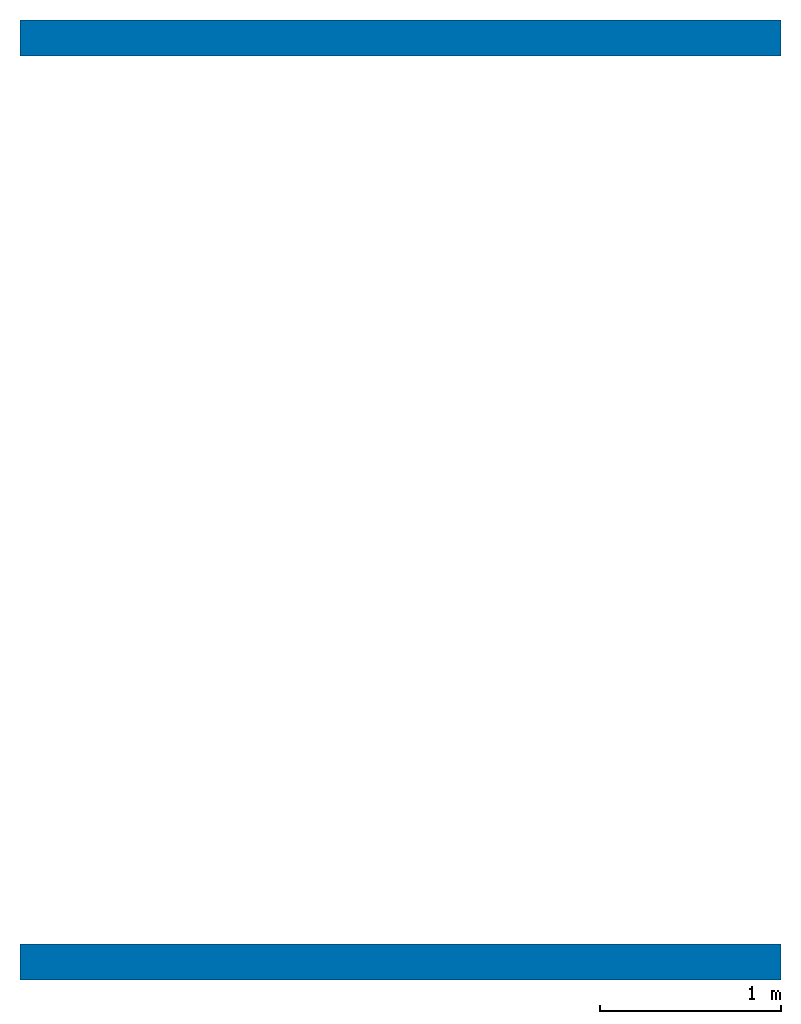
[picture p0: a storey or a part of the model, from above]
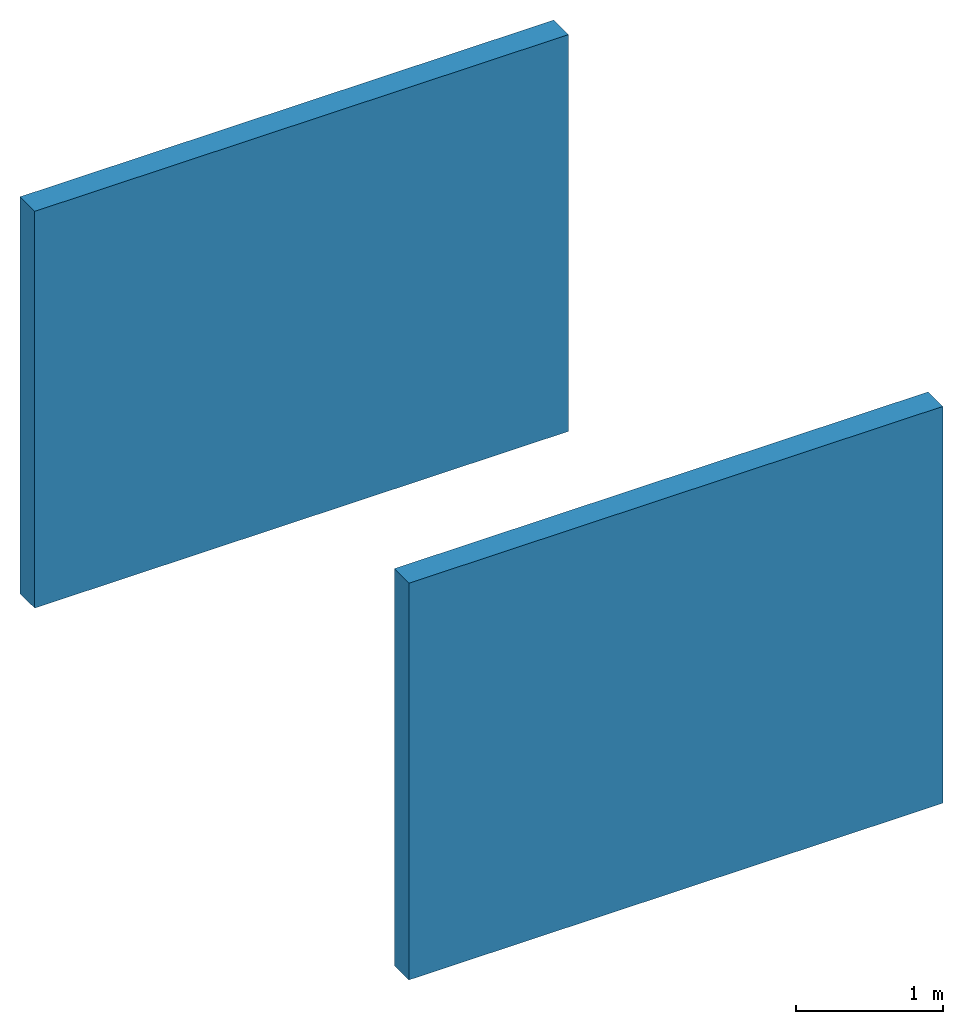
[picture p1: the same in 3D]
Properties of the parts of a building model (IFC4)

# File
Description: ViewDefinition [ReferenceView_V1.2], RevitIdentifiers [ContentGUID: , VersionGUID: 488d4783-6c16-4759-8540-48bcfd5ee86a, NumberOfSaves: 76], CoordinateReference [CoordinateBase: Project Base Point, ProjectSite: Internal]
File name: [V-code]_([context]-[cluster]-[discipline])_(concept-aanzet).ifc
Time: 2025-09-28T15:26:29+01:00
Written by: ODA SDAI 22.12
Made in: Autodesk Revit 23.1.80.30 (ENU) - IFC 23.4.1.0

# IfcProject, [ProjectCode]
LongName: [ProjectNaam]
RBS - Name: [ProjectCode]; LongName: [ProjectNaam]; OS link: [OS link]

# IfcSite, [ComplexCode]
LongName: [ComplexNaam]; RefLatitude: 52, 4, 57, 468566; RefLongitude: 4, 19, 1, 452026; RefElevation: 0 mm
Pset_SiteCommon - Reference: Project Information
RBS - Name: [ComplexCode]; LongName: [ComplexNaam]; SiteAddress: [Straatnaam] [Huisnummer] [Huisnummer toev.],[Postcode] [Plaatsnaam],[Land]; TrueNorth: 0 deg
Other - Category: Project Information; Project Address: [Straatnaam] [Huisnummer] [Huisnummer toev.],[Postcode] [Plaatsnaam],[Land]; Project Name: [ProjectNaam]; Project Number: [ProjectCode]
Constraints - TrueNorth: 0 deg
Data - RBS_OS_link: [OS link]
Identity Data - BuildingLongName: [BouwwerkNaam]; Building Name: [BouwwerkCode]; RBS_opdrachtnemer_bedrijf_adres: [ON BedrijfsAdres]; RBS_opdrachtnemer_bedrijf_naam: [ON BedrijfsNaam]; RBS_opdrachtnemer_project_code: [ON ProjectCode]; RBS_vastgoed_deel_code: [BouwwerkDeelCode]; SiteLongName: [ComplexNaam]; SiteName: [ComplexCode]

# IfcBuilding, [BouwwerkCode]
LongName: [BouwwerkNaam]
Pset_BuildingCommon - Reference: Project Information; NumberOfStoreys: 4
Pset_BuildingElementProxyCommon - Reference: Project Information; IsExternal: no
Pset_BuildingStoreyCommon - Reference: Project Information; sets with these values: 2
RBS - Name: [BouwwerkCode]; LongName: [BouwwerkNaam]
Other - Category: Project Information; Project Address: [Straatnaam] [Huisnummer] [Huisnummer toev.],[Postcode] [Plaatsnaam],[Land]; Project Name: [ProjectNaam]; Project Number: [ProjectCode]
Constraints - TrueNorth: 0 deg
Data - RBS_OS_link: [OS link]
Identity Data - BuildingLongName: [BouwwerkNaam]; Building Name: [BouwwerkCode]; RBS_opdrachtnemer_bedrijf_adres: [ON BedrijfsAdres]; RBS_opdrachtnemer_bedrijf_naam: [ON BedrijfsNaam]; RBS_opdrachtnemer_project_code: [ON ProjectCode]; RBS_vastgoed_deel_code: [BouwwerkDeelCode]; SiteLongName: [ComplexNaam]; SiteName: [ComplexCode]

# IfcBuildingStorey: bouwlaag (4)
In: [BouwwerkCode]
Pset_BuildingStoreyCommon - EntranceLevel: no
RBS - Structural: no
Other - Category: Levels; Family: Level
Data - EntranceLevel: no
Dimensions - Computation Height: 0 mm
Identity Data - Structural: no
Other(Type) - Category: Levels; Family Name: Level
Constraints(Type) - Elevation Base: Project Base Point
Graphics(Type) - Line Pattern: Dash=2_Space=1_Dot_Space=1; Line Weight: 1
Name | LongName | Elevation (mm) = RBS, Elevation (mm) = Constraints, Elevation (mm) | Reference = Type = Type Name | Pset_BuildingStoreyCommon, AboveGround = Data, AboveGround | RBS, Name = IfcName | RBS, LongName = IfcLongName | Family and Type | Type Id | Building Story = Symbol at End 1 Default | Identity Data, Name | Color | Symbol | Symbol at End 2 Default | IfcObjectType[Type]
-1 | kelder | -3300 | vloer-afgewerkt-BK_bouwlaag | no | -1 | kelder | Level: vloer-afgewerkt-BK_bouwlaag | 2863 | yes | -1_kelder_(AVL-BK) | 13073152 | RBS_--_LAB_Elevation Head : AVL-BK | no | bouwlaag | Constraints - Story Above: 00_begane grond_(AVL-BK)
00 | begane grond | 0 | maaiveld | yes |  |  | Level: maaiveld | 2905 | no | terrein | 821049 | RBS_--_LAB_Elevation Head : MV | yes
01 | verdieping | 3300 | vloer-afgewerkt-BK_bouwlaag | yes | 01 | verdieping | Level: vloer-afgewerkt-BK_bouwlaag | 2863 | yes | 01_eerste verdieping_(AVL-BK) | 13073152 | RBS_--_LAB_Elevation Head : AVL-BK | no | bouwlaag | Constraints - Story Above: 02_tweede verdieping_(AVL-BK)
02 | verdieping | 6600 | vloer-afgewerkt-BK_bouwlaag | yes | 02 | verdieping | Level: vloer-afgewerkt-BK_bouwlaag | 2863 | yes | 02_tweede verdieping_(AVL-BK) | 13073152 | RBS_--_LAB_Elevation Head : AVL-BK | no | bouwlaag

# IfcBuildingStorey: bouwlaag_tussen, 01t
In: [BouwwerkCode]
LongName: tussenverdieping; Elevation: 4800 mm
Pset_BuildingStoreyCommon - EntranceLevel: no; AboveGround: yes; Reference: vloer-afgewerkt-BK_bouwlaag_tussen
RBS - Structural: no; Name: 01t; LongName: tussenverdieping; Elevation: 4800 mm
Other - Category: Levels; Family: Level; Family and Type: Level: vloer-afgewerkt-BK_bouwlaag_tussen; Type: vloer-afgewerkt-BK_bouwlaag_tussen; Type Id: 2880
Constraints - Elevation: 4800 mm
Data - EntranceLevel: no; AboveGround: yes
Dimensions - Computation Height: 0 mm
Identity Data - Structural: no; Building Story: yes; IfcLongName: tussenverdieping; IfcName: 01t; Name: 01t_eerste verdieping_(AVL-BK)
Other(Type) - Category: Levels; Family Name: Level
Constraints(Type) - Elevation Base: Project Base Point
Graphics(Type) - Line Pattern: Dash=2_Space=1_Dot_Space=1; Line Weight: 1; Symbol: RBS_--_LAB_Elevation Head : AVL-BK; Symbol at End 1 Default: yes; Symbol at End 2 Default: no; Color: 13073152
Identity Data(Type) - IfcObjectType[Type]: bouwlaag_tussen; Type Name: vloer-afgewerkt-BK_bouwlaag_tussen

# IfcBuildingStorey: bouwlaagoppervlaklaag (2)
In: [BouwwerkCode]
Pset_BuildingStoreyCommon - EntranceLevel: no; Reference: registratief-oppervlak; AboveGround: yes
RBS - Structural: no
Other - Category: Levels; Family: Level; Family and Type: Level: registratief-oppervlak; Type: registratief-oppervlak; Type Id: 2917
Data - EntranceLevel: no; AboveGround: yes
Dimensions - Computation Height: 0 mm
Identity Data - Structural: no; Building Story: yes
Other(Type) - Category: Levels; Family Name: Level
Constraints(Type) - Elevation Base: Project Base Point
Graphics(Type) - Line Pattern: Dash=2_Space=1_Dot_Space=1; Line Weight: 1; Symbol at End 1 Default: yes; Symbol at End 2 Default: no; Color: 13073152; Symbol: RBS_--_LAB_Elevation Head : RO
Identity Data(Type) - IfcObjectType[Type]: bouwlaagoppervlaklaag; Type Name: registratief-oppervlak
Name | LongName = Identity Data, Name | Elevation (mm) = RBS, Elevation (mm) = Constraints, Elevation (mm) | RBS, Name = IfcName
00 | 00_bouwlaagoppervlak | 0 | 00 | Constraints - Story Above: 01_bouwlaagoppervlak
01 | 01_bouwlaagoppervlak | 3300 | 01

# IfcSpace: 00.001 (2)
In: 00
Pset_SpaceCommon - IsExternal: no
RBS - IsExternal: no; Name: 00.001
Qto_SpaceBaseQuantities - Height: 3300 mm
Construction - IsExternal: no
Dimensions - Computation Height: 0 mm
Identity Data - IfcName: 00.001; Number: 00.001 (projectspecifiek)
Name | LongName = RBS, LongName = ObjectType = IfcLongName = IfcObjectType | Pset_SpaceCommon, Reference = Pset_SpaceHeaterTypeCommon, Reference | ElementId | GrossFloorArea (m2) = NetFloorArea (m2) = GrossCeilingArea (m2) = Area (m2) | Category | Level | Perimeter (mm) | Name
00.001 | ruimte | ruimte (projectspecifiek) 00.001 (projectspecifiek) | 697761 | 19.6 | Rooms | 00_begane grond_(AVL-BK) | 17800 | ruimte (projectspecifiek) | Qto_SpaceBaseQuantities - GrossVolume: 58.8 m3; NetVolume: 58.8 m3; Other - Phase Id: 3; Constraints - Base Offset: 0 mm; Limit Offset: 0 mm; Upper Limit: 01_eerste verdieping_(AVL-BK); Dimensions - Unbounded Height: 3300 mm; Volume: 58.8 m3; Energy Analysis - Actual Lighting Load: 0 W; Actual Lighting Load per area: 0; Actual Power Load: 0 W; Actual Power Load per area: 0; Area per Person: 28.5714 m2; Base Lighting Load on: By Space Type; Base Power Load on: By Space Type; Heat Load Values: By Space Type; Latent Heat Gain per person: 58.6142 W; Lighting Load Units: Power Density; Number of People: 0; Plenum Lighting Contribution: 0.2; Power Load Units: Power Density; Sensible Heat Gain per person: 73.2678 W; Specified Lighting Load: 0 W; Specified Lighting Load per area: 10.7639; Specified Power Load: 0 W; Specified Power Load per area: 13.9931; Total Heat Gain per person: 131.882 W; Phasing - Phase: nieuw
00.001 | bouwlaagoppervlak | bouwlaagoppervlak (projectspecifiek) 00.001 (projectspecifiek) | 697809 | 22.26 | Areas | 00_bouwlaagoppervlak | 19000 | bouwlaagoppervlak (projectspecifiek) | Other - Area Scheme Id: 2033; Area Type: Gross Building Area; Group: Gross Building

# IfcAirTerminal: Air Terminals : RBS_57_AT_ventilatierooster_BUVA_SH : Acoustream_65
In: 00
Type - PredefinedType: GRILLE; Classification: 57.10 luchtbehandeling; natuurlijk, algemeen (verzamelniveau) (NL-SfB); Material: divers
Type - Other - Category: Air Terminals; Family Name: RBS_57_AT_ventilatierooster_BUVA_SH
Type - Constraints - Default Elevation: 0.0131234 mm
Type - Dimensions - ventilatierooster_dikte: 15 mm; ventilatierooster_hoogte: 67.2153 mm; ventilatierooster_stelruimte_hout: 5 mm
Type - Identity Data - Assembly Code: 57.10; Assembly Description: luchtbehandeling; natuurlijk, algemeen (verzamelniveau); Description: PD-06022-Acoustream-65; IfcObjectType[Type]: ventilatierooster; Manufacturer: BUVA; Type Name: Acoustream_65
Type - Materials and Finishes - materiaal_onderdorpel: RBS_divers_gen
Type - Structural - LoadBearing: no; Structural: no
Type - Pset_ManufacturerTypeInformation - Manufacturer: BUVA
Type - RBS - IsExternal: yes; LoadBearing: no; Description: PD-06022-Acoustream-65; ObjectType: ventilatierooster; PredefinedType: GRILLE; Class: IfcAirTerminalType
Pset_AirTerminalBoxTypeCommon - Reference: Acoustream_65; sets with these values: 3
Qto_AirTerminalBaseQuantities - Perimeter: 457.047 mm
Other - Family: RBS_57_AT_ventilatierooster_BUVA_SH; Family and Type: RBS_57_AT_ventilatierooster_BUVA_SH: Acoustream_65; Type: Acoustream_65; Type Id: 645236
Constraints - Level: 00_begane grond_(AVL-BK); Moves With Nearby Elements: no; Elevation from Level: 2452.78 mm; Host: Level : 00_begane grond_(AVL-BK); Offset from Host: 2452.78 mm
Dimensions - Area: 0.212508 m2; kozijn_inbouwmaat: 900 mm; ventilatierooster_lengte: 890 mm; Volume: 0.0081186 m3
Identity Data - Assembly Name: kozijncombinatie_buiten; Mark: 2
Phasing - Phase Created: nieuw

# IfcBuildingElementProxy: Generic Models : RBS_--_GM_coördinatiepunt : peildatum_UIT, coördinatiepunt
In: [ComplexCode]
Type - PredefinedType: USERDEFINED; Classification: --.-- niet van toepassing (NL-SfB); Material: generiek - kleur (2)
Type - Other - Category: Generic Models; Family Name: RBS_--_GM_coördinatiepunt
Type - Dimensions - discipline_dikte: 25 mm
Type - Graphics - zichtbaar_discipline_B: no; zichtbaar_discipline_C: no; zichtbaar_discipline_E: no; zichtbaar_discipline_W: no; zichtbaar_peildatum: no
Type - Identity Data - Assembly Code: --.--; Assembly Description: niet van toepassing; IfcObjectType[Type]: coördinatiepunt; Type Name: peildatum_UIT
Type - Materials and Finishes - materiaal_discipline: RBS_kleur_wit_RGB (255-255-255); materiaal_kubus_basis: RBS_kleur_blauw_RGB (000-123-199); materiaal_kubus_hoek: RBS_kleur_rood_RGB (213-043-030); materiaal_peildatum: RBS_kleur_wit_RGB (255-255-255)
Type - RBS - ObjectType: coördinatiepunt; PredefinedType: USERDEFINED; Class: IfcBuildingElementProxyType
Pset_BuildingElementProxyCommon - IsExternal: no; Reference: peildatum_UIT
Pset_EnvironmentalImpactIndicators - Reference: peildatum_UIT
RBS - Name: coördinatiepunt; ElementId: 692979; SpatialContainer: IfcSite
Qto_BuildingElementProxyQuantities - NetSurfaceArea: 6.06928 m2; NetVolume: 1 m3
Other - Family: RBS_--_GM_coördinatiepunt; Family and Type: RBS_--_GM_coördinatiepunt: peildatum_UIT; Type: peildatum_UIT; Type Id: 692949
Constraints - Elevation from Level: 0 mm; Moves With Nearby Elements: no; Offset from Host: 0 mm; Host: Level : projectpeil=0; IfcSpatialContainer: IfcSite; Level: projectpeil=0
Data - RBS_VIP_datum_peil: dd-mm-jjjj
Dimensions - Area: 3.26796 m2; Volume: 1 m3
Identity Data - IfcName: coördinatiepunt
Phasing - Phase Created: nieuw

# IfcDoor: Doors : RBS_31_DO_deur_buiten_stomp_glas_1_paneel_SH : linksdraaiend
In: 00
Type - PredefinedType: DOOR; OperationType: SINGLE_SWING_RIGHT; Classification: 31.40 buitenwandopeningen; gevuld met puien, algemeen (verzamelniveau) (NL-SfB); Material: glas, hout
Type - Doors : RBS_31_DO_deur_buiten_stomp_glas_1_paneel_SH : linksdraaiend:1 - PanelOperation: SWINGING
Type - Other - Category: Doors; draairichting: RBS_3-_GM_deur_stomp_glas_draairichting_N : linksdraaiend; Family Name: RBS_31_DO_deur_buiten_stomp_glas_1_paneel_SH
Type - Constraints - Default Elevation: 0 mm
Type - Construction - Function: Exterior
Type - Identity Data - Assembly Code: 31.40; Assembly Description: buitenwandopeningen; gevuld met puien, algemeen (verzamelniveau); IfcExportAs[Type]: IfcDoor; IfcObjectType[Type]: deur; Type Mark: 11; Type Name: linksdraaiend
Type - Analytical Properties - Define Thermal Properties by: Schematic Type; Analytic Construction: <None>
Type - RBS - IsExternal: yes; ObjectType: deur; OperationType: SINGLE_SWING_RIGHT; Class: IfcDoor
OverallHeight: 1010 mm; OverallWidth: 930 mm
Pset_DoorCommon - IsExternal: yes; Reference: linksdraaiend
Pset_EnvironmentalImpactIndicators - Reference: linksdraaiend
Qto_DoorBaseQuantities - Width: 2015 mm; Height: 930 mm; Perimeter: 5890 mm; Area: 2.31905 m2
Other - Family: RBS_31_DO_deur_buiten_stomp_glas_1_paneel_SH; Family and Type: RBS_31_DO_deur_buiten_stomp_glas_1_paneel_SH: linksdraaiend; Type: linksdraaiend; Type Id: 645223
Constraints - Level: 00_begane grond_(AVL-BK); Moves With Nearby Elements: no; Host: Level : 00_begane grond_(AVL-BK); Offset from Host: 80 mm
Dimensions - Area: 2.31905 m2; b_glas: 630 mm; b_paneel: 930 mm; b_paneel_bovendorpel: 150 mm; b_paneel_onderdorpel: 400 mm; b_paneel_stijlen: 150 mm; d_glas: 20 mm; d_paneel: 80 mm; h_glas: 1465 mm; h_paneel: 2015 mm; Volume: 0.094539 m3
Identity Data - Assembly Name: kozijncombinatie_buiten; Mark: 1
Materials and Finishes - materiaal_glas: RBS_glas_afwerking_dubbel glas_floatglas; materiaal_paneel: RBS_hout_massief_vuren
Phasing - Phase Created: nieuw

# IfcElementAssembly: Assemblies : Generic Models Assembly : kozijncombinatie_buiten
In: 00
Type - Other - Category: Assemblies; Family Name: Generic Models Assembly
Type - Construction - IsExternal[Type]: yes
Type - Identity Data - Assembly Code: 31.40; Assembly Description: buitenwandopeningen; gevuld met puien, algemeen (verzamelniveau); IfcObjectType[Type]: kozijncombinatie; Type Name: kozijncombinatie_buiten
Type - RBS - IsExternal: yes; ObjectType: kozijncombinatie; Class: IfcElementAssemblyType
Classification: 31.40 buitenwandopeningen; gevuld met puien, algemeen (verzamelniveau) (NL-SfB)
Pset_ElementAssemblyCommon - Reference: kozijncombinatie_buiten; sets with these values: 2
RBS - ElementId: 644300; SpatialContainer: 00_begane grond_(AVL-BK)
Other - Family: Generic Models Assembly; Family and Type: Generic Models Assembly: kozijncombinatie_buiten; Type: kozijncombinatie_buiten; Type Id: 645158
Constraints - IfcSpatialContainer: 00_begane grond_(AVL-BK)
Identity Data - Naming Category: Generic Models
Phasing - Phase Created: nieuw

# IfcGroup, Gross Building
Other - Category: Area Schemes; Name: Gross Building

# IfcMember: Generic Models : RBS_3-_GM_pui_onderdorpel_SH : buiten
In: 00
Type - PredefinedType: USERDEFINED; Classification: 31.40 buitenwandopeningen; gevuld met puien, algemeen (verzamelniveau) (NL-SfB); Material: hout
Type - Other - Category: Generic Models; Family Name: RBS_3-_GM_pui_onderdorpel_SH
Type - Construction - IsExternal[Type]: yes
Type - Identity Data - Assembly Code: 31.40; Assembly Description: buitenwandopeningen; gevuld met puien, algemeen (verzamelniveau); IfcExportAs[Type]: IfcMember; IfcObjectType[Type]: dorpel; Type Mark: 14; Type Name: buiten
Type - Pset_MemberCommon - IsExternal: yes
Type - RBS - IsExternal: yes; ObjectType: dorpel; PredefinedType: USERDEFINED; Class: IfcMember
Pset_EnvironmentalImpactIndicators - Reference: buiten
Pset_MemberCommon - Reference: buiten
Qto_MemberBaseQuantities - Length: 80 mm; CrossSectionArea: 0.45 m2; OuterSurfaceArea: 0.6192 m2; GrossSurfaceArea: 1.5192 m2; NetSurfaceArea: 1.5192 m2; GrossVolume: 0.036 m3; NetVolume: 0.036 m3
Other - Type: buiten; Family: RBS_3-_GM_pui_onderdorpel_SH; Family and Type: RBS_3-_GM_pui_onderdorpel_SH: buiten; Type Id: 645228
Constraints - Elevation from Level: 0 mm; Level: 00_begane grond_(AVL-BK); Moves With Nearby Elements: no; Host: Level : 00_begane grond_(AVL-BK); Offset from Host: 0 mm
Dimensions - Area: 0.7596 m2; b_kozijn: 3750 mm; b_kozijn_onderdorpel: 80 mm; d_kozijn: 120 mm; Volume: 0.036 m3
Identity Data - Assembly Name: kozijncombinatie_buiten
Materials and Finishes - materiaal_kozijn: RBS_hout_massief_eiken
Phasing - Phase Created: nieuw

# IfcMember: Generic Models : RBS_31_GM_pui_buiten_1 : pui-bxhxd=3750x2600x120
In: 00
Type - PredefinedType: USERDEFINED; Classification: 31.40 buitenwandopeningen; gevuld met puien, algemeen (verzamelniveau) (NL-SfB); Material: hout
Type - Other(Type) - Category: Generic Models; Family Name: RBS_31_GM_pui_buiten_1
Type - Constraints(Type) - Default Elevation: 0 mm
Type - Construction(Type) - IsExternal[Type]: yes
Type - Dimensions(Type) - b_deur_paneel_bovendorpel: 150 mm; b_deur_paneel_onderdorpel: 400 mm; b_deur_paneel_stijlen: 150 mm; b_dorpel_1: 1925 mm; b_dorpel_2: 895 mm; b_kozijn_dorpel: 80 mm; b_kozijn_onderdorpel: 80 mm; b_kozijn_stijlen: 80 mm; b_overstek: 15 mm; b_paneel_1: 750 mm; b_paneel_2: 900 mm; b_paneel_3: 800 mm; b_paneel_4: 900 mm; b_pui: 3750 mm; b_raam_paneel_roedes: 60 mm; b_raam_paneel_stijlen: 70 mm; berekening_b_paneel_1: 780 mm; berekening_b_paneel_2: 930 mm; berekening_b_paneel_3: 830 mm; berekening_b_paneel_4: 930 mm; berekening_h_paneel_2a: 390 mm; berekening_h_paneel_2b: 2015 mm; berekening_h_paneel_4a: 1560 mm; berekening_h_paneel_4b: 630 mm; d_glas: 20 mm; d_paneel: 80 mm; d_pui: 120 mm; h_paneel: 2390 mm; h_paneel_2a: 360 mm; h_paneel_2b: 2000 mm; h_paneel_4a: 1680 mm; h_paneel_4b: 600 mm; h_paneel_4c: 150 mm; h_pui: 2600 mm; h_ventilatierooster: 125 mm; offset: 0 mm
Type - Identity Data(Type) - Assembly Code: 31.40; Assembly Description: buitenwandopeningen; gevuld met puien, algemeen (verzamelniveau); IfcExportAs[Type]: IfcMember; IfcObjectType[Type]: kozijn; Type Name: pui-bxhxd=3750x2600x120
Type - Materials and Finishes(Type) - materiaal_glas: RBS_glas_afwerking_dubbel glas_floatglas; materiaal_kozijn: RBS_hout_massief_vuren; materiaal_onderdorpel: RBS_hout_massief_eiken; materiaal_paneel: RBS_hout_massief_vuren; materiaal_ventilatierooster: RBS_staal_massief_gegalvaniseerd
Type - Pset_MemberCommon - IsExternal: yes
Type - RBS - IsExternal: yes; ObjectType: kozijn; PredefinedType: USERDEFINED; Class: IfcMember
Pset_EnvironmentalImpactIndicators - Reference: pui-bxhxd=3750x2600x120
Pset_MemberCommon - Reference: pui-bxhxd=3750x2600x120
RBS - ElementId: 644291
Qto_MemberBaseQuantities - CrossSectionArea: 4.3349 m2; NetSurfaceArea: 8.6698 m2; NetVolume: 0.16638 m3
Other - Category: Generic Models; Family: RBS_31_GM_pui_buiten_1; Family and Type: RBS_31_GM_pui_buiten_1: pui-bxhxd=3750x2600x120; Host Id: 644290; Type: pui-bxhxd=3750x2600x120; Type Id: 645156
Constraints - draairichting_deur: RBS_31_DO_deur_buiten_stomp_glas_1_paneel_SH : linksdraaiend; draairichting_raam_4: RBS_3-_WI_raam_paneel_SH : links_buiten; Elevation from Level: 0 mm; Level: 00_begane grond_(AVL-BK); offset_pui: 100 mm
Dimensions - Area: 4.3349 m2; offset_a: 100 mm; offset_b: 200 mm; Volume: 0.16638 m3
Identity Data - Assembly Name: kozijncombinatie_buiten
Phasing - Phase Created: nieuw

# IfcOpeningElement, Walls : Basic Wall : RBS_21_WA_wand_buiten_d=200
In: 00
PredefinedType: OPENING; Classification: 31.40 buitenwandopeningen; gevuld met puien, algemeen (verzamelniveau) (NL-SfB)
Qto_OpeningElementBaseQuantities - Depth: 3048 mm; Height: 2600 mm; Width: 3750 mm
Pset_EnvironmentalImpactIndicators - Reference: pui-bxhxd=3750x2600x120; sets with these values: 2
RBS - ElementId: 644291
Other - Category: Generic Models; Family: RBS_31_GM_pui_buiten_1; Family and Type: RBS_31_GM_pui_buiten_1: pui-bxhxd=3750x2600x120; Host Id: 644290; Type: pui-bxhxd=3750x2600x120; Type Id: 645156
Constraints - draairichting_deur: RBS_31_DO_deur_buiten_stomp_glas_1_paneel_SH : linksdraaiend; draairichting_raam_4: RBS_3-_WI_raam_paneel_SH : links_buiten; Elevation from Level: 0 mm; Level: 00_begane grond_(AVL-BK); offset_pui: 100 mm
Dimensions - Area: 4.3349 m2; offset_a: 100 mm; offset_b: 200 mm; Volume: 0.16638 m3
Identity Data - Assembly Name: kozijncombinatie_buiten
Phasing - Phase Created: nieuw

# IfcPlate: Windows : RBS_3-_WI_pui_paneel_SH : buiten
In: 00
Type - PredefinedType: USERDEFINED; Classification: 31.40 buitenwandopeningen; gevuld met puien, algemeen (verzamelniveau) (NL-SfB); Material: hout
Type - Other - Category: Windows; Family Name: RBS_3-_WI_pui_paneel_SH
Type - Constraints - Default Elevation: 0 mm
Type - Construction - IsExternal[Type]: yes
Type - Identity Data - Assembly Code: 31.40; Assembly Description: buitenwandopeningen; gevuld met puien, algemeen (verzamelniveau); IfcExportAs[Type]: IfcPlate; IfcObjectType[Type]: paneel; Type Mark: 24; Type Name: buiten
Type - Analytical Properties - Define Thermal Properties by: Schematic Type; Analytic Construction: <None>
Type - Pset_PlateCommon - IsExternal: yes
Type - RBS - IsExternal: yes; ObjectType: paneel; PredefinedType: USERDEFINED; Class: IfcPlate
Pset_EnvironmentalImpactIndicators - Reference: buiten
Pset_PlateCommon - Reference: buiten
Qto_PlateBaseQuantities - Width: 80 mm; Perimeter: 1820 mm; GrossArea: 0.0664 m2; NetArea: 2.2413 m2; GrossVolume: 0.158696 m3; NetVolume: 0.158696 m3
Other - Type: buiten; Family: RBS_3-_WI_pui_paneel_SH; Family and Type: RBS_3-_WI_pui_paneel_SH: buiten; Type Id: 645222
Constraints - Level: 00_begane grond_(AVL-BK); Moves With Nearby Elements: no; Host: Level : 00_begane grond_(AVL-BK); Offset from Host: 145 mm
Dimensions - Area: 2.2413 m2; b_paneel: 830 mm; d_paneel: 80 mm; h_paneel: 2390 mm; Volume: 0.158696 m3
Identity Data - Assembly Name: kozijncombinatie_buiten; Mark: 2
Materials and Finishes - materiaal_vlakvulling: RBS_hout_massief_vuren
Phasing - Phase Created: nieuw

# IfcSlab: Floors : Floor : RBS_23_FL_vloer_binnen_d=300 (2)
Type - PredefinedType: FLOOR; Material: beton (2)
Type - Other - Category: Floors; Family Name: Floor
Type - Construction - Function: Interior; Default Thickness: 300 mm
Type - Graphics - Coarse Scale Fill Color: 0
Type - Identity Data - Assembly Code: 23.20; Assembly Description: vloeren; constructief, algemeen (verzamelniveau); IfcObjectType[Type]: vloer; Type Name: RBS_23_FL_vloer_binnen_d=300
Type - Analytical Properties - Absorptance: 0.1; Roughness: 1
Type - RBS - IsExternal: no; ObjectType: vloer; Class: IfcSlabType
Classification: 23.20 vloeren; constructief, algemeen (verzamelniveau) (NL-SfB)
Pset_EnvironmentalImpactIndicators - Reference: RBS_23_FL_vloer_binnen_d=300; sets with these values: 2
Pset_SlabCommon - IsExternal: no; LoadBearing: yes; Reference: RBS_23_FL_vloer_binnen_d=300; PitchAngle: 0 deg
RBS - LoadBearing: yes
Qto_SlabBaseQuantities - beton, Width: 50 mm; beton (2), Width: 250 mm; Width: 300 mm; Length: 5100 mm; Depth: 250 mm; Perimeter: 61.0236 mm; GrossArea: 21.42 m2; NetArea: 21.42 m2; GrossVolume: 5.355 m3; NetVolume: 6.426 m3
Other - Family: Floor; Family and Type: Floor: RBS_23_FL_vloer_binnen_d=300; Type: RBS_23_FL_vloer_binnen_d=300; Type Id: 691724
Constraints - Related to Mass: no; Room Bounding: yes; Height Offset From Level: 0 mm
Dimensions - Area: 21.42 m2; Core Thickness: 300 mm; Perimeter: 18600 mm; Thickness: 300 mm; Volume: 6.426 m3
Identity Data - Has Association: no
Phasing - Phase Created: nieuw
Structural - Structural: yes; Rebar Cover - Other Faces: Rebar Cover 1 <25 mm>; Rebar Cover - Bottom Face: Rebar Cover 1 <25 mm>; Rebar Cover - Top Face: Rebar Cover 1 <25 mm>
Name (Floors : Floor :...) | In | ElementId | Level | Elevation at Bottom (mm) = Elevation at Bottom Core (mm) = Elevation at Bottom Survey (mm) | Elevation at Top (mm) = Elevation at Top Core (mm) = Elevation at Top Survey (mm)
 RBS_23_FL_vloer_binnen_d=300 | 01 | 691708 | 01_eerste verdieping_(AVL-BK) | 3000 | 3300
 RBS_23_FL_vloer_binnen_d=300 | 00 | 691715 | 00_begane grond_(AVL-BK) | -300 | 0

# IfcWall: Walls : Basic Wall : RBS_21_WA_wand_buiten_d=200 (7)
Type - PredefinedType: STANDARD
Type - Other - Category: Walls; Family Name: Basic Wall
Type - Construction - Function: Exterior; Width: 200 mm; Wrapping at Inserts: Do not wrap
Type - Graphics - Coarse Scale Fill Color: 0
Type - Identity Data - Assembly Code: 21.20; Assembly Description: buitenwanden; constructief, algemeen (verzamelniveau); IfcObjectType[Type]: wand; Type Name: RBS_21_WA_wand_buiten_d=200
Type - Analytical Properties - Absorptance: 0.1; Roughness: 1
Type - RBS - IsExternal: yes; ObjectType: wand; Class: IfcWallType
Classification: 21.20 buitenwanden; constructief, algemeen (verzamelniveau) (NL-SfB); Material: beton
Qto_WallBaseQuantities - Width: 200 mm
Pset_EnvironmentalImpactIndicators - Reference: RBS_21_WA_wand_buiten_d=200; sets with these values: 2
Pset_WallCommon - Reference: RBS_21_WA_wand_buiten_d=200; IsExternal: yes; LoadBearing: yes
RBS - LoadBearing: yes
Other - Family: Basic Wall; Family and Type: Basic Wall: RBS_21_WA_wand_buiten_d=200; Type: RBS_21_WA_wand_buiten_d=200; Type Id: 691693
Constraints - Base Extension Distance: 0 mm; Base is Attached: no; Location Line: Finish Face: Interior; Related to Mass: no; Room Bounding: yes; Top Extension Distance: 0 mm; Top Offset: 0 mm
Identity Data - Has Association: no
Phasing - Phase Created: nieuw
Structural - Structural: yes; Structural Usage: Bearing
Cross-Section Definition - Cross-Section: Vertical
Name (Walls : Basic Wall :...) | In | Height (mm) = Unconnected Height (mm) | Qto_WallBaseQuantities, Length (mm) | GrossFootprintArea (m2) | GrossVolume (m3) = NetVolume (m3) = Volume (m3) | GrossSideArea (m2) = NetSideArea (m2) = Area (m2) | ExtendToStructure = Top is Attached | ElementId | Base Offset (mm) | Base Constraint | Top Constraint | Dimensions, Length (mm) | Rebar Cover - Exterior Face = Rebar Cover - Interior Face | Rebar Cover - Other Faces
 RBS_21_WA_wand_buiten_d=200 | 00 | 3000 | 6000 | 1.2 | 1.65 | 8.25 | no | 644290 | 0 | 00_begane grond_(AVL-BK) | Up to level: 01_eerste verdieping_(RVL-OK) | 6000 | XC1 - plaat / wand <15 mm> | XC1 - plaat / wand <15 mm>
 RBS_21_WA_wand_buiten_d=200 | -1 | 3300 | 4200 | 0.84 | 2.772 | 13.86 | yes | 691690 | -300 | -1_kelder_(AVL-BK) | Up to level: 00_begane grond_(RVL-OK) | 4200 | Rebar Cover 1 <25 mm> | Rebar Cover 1 <25 mm>
 RBS_21_WA_wand_buiten_d=200 | -1 | 3300 | 4200 | 0.84 | 2.772 | 13.86 | yes | 691691 | -300 | -1_kelder_(AVL-BK) | Up to level: 00_begane grond_(RVL-OK) | 4200 | Rebar Cover 1 <25 mm> | Rebar Cover 1 <25 mm>
 RBS_21_WA_wand_buiten_d=200 | 00 | 3300 | 4200 | 0.84 | 2.772 | 13.86 | yes | 691702 | -300 | 00_begane grond_(AVL-BK) | Up to level: 01_eerste verdieping_(RVL-OK) | 4100 | Rebar Cover 1 <25 mm>
 RBS_21_WA_wand_buiten_d=200 | 00 | 3300 | 4200 | 0.84 | 2.772 | 13.86 | yes | 691704 | -300 | 00_begane grond_(AVL-BK) | Up to level: 01_eerste verdieping_(RVL-OK) | 4100 | Rebar Cover 1 <40 mm> | Rebar Cover 1 <40 mm>
 RBS_21_WA_wand_buiten_d=200 | 01 | 3300 | 4200 | 0.84 | 2.772 | 13.86 | no | 692048 | -300 | 01_eerste verdieping_(AVL-BK) | Up to level: 02_tweede verdieping_(RVL-OK) | 4200 | Rebar Cover 1 <40 mm> | Rebar Cover 1 <40 mm>
 RBS_21_WA_wand_buiten_d=200 | 01 | 3300 | 4200 | 0.84 | 2.772 | 13.86 | no | 692049 | -300 | 01_eerste verdieping_(AVL-BK) | Up to level: 02_tweede verdieping_(RVL-OK) | 4200 | Rebar Cover 1 <40 mm> | Rebar Cover 1 <40 mm>

# IfcWall: Walls : Basic Wall : RBS_22_WA_wand_binnen_d=100 (2)
In: 00
Type - PredefinedType: STANDARD
Type - Other - Category: Walls; Family Name: Basic Wall
Type - Construction - Wrapping at Inserts: Do not wrap; Function: Interior; Width: 100 mm
Type - Graphics - Coarse Scale Fill Color: 0
Type - Identity Data - Assembly Code: 22.10; Assembly Description: binnenwanden; niet constructief, algemeen (verzamelniveau); IfcObjectType[Type]: wand; Type Name: RBS_22_WA_wand_binnen_d=100
Type - Analytical Properties - Absorptance: 0.1; Roughness: 1
Type - RBS - IsExternal: no; ObjectType: wand; Class: IfcWallType
Classification: 22.10 binnenwanden; niet constructief, algemeen (verzamelniveau) (NL-SfB); Material: <Unnamed>
Qto_WallBaseQuantities - Height: 3000 mm; Length: 4900 mm; Width: 100 mm; GrossFootprintArea: 0.49 m2; GrossVolume: 1.47 m3; GrossSideArea: 14.7 m2; NetSideArea: 14.7 m2; NetVolume: 1.47 m3
Pset_EnvironmentalImpactIndicators - Reference: RBS_22_WA_wand_binnen_d=100; sets with these values: 2
Pset_WallCommon - IsExternal: no; LoadBearing: no; ExtendToStructure: yes; Reference: RBS_22_WA_wand_binnen_d=100
RBS - LoadBearing: no
Other - Family: Basic Wall; Family and Type: Basic Wall: RBS_22_WA_wand_binnen_d=100; Type: RBS_22_WA_wand_binnen_d=100; Type Id: 691722
Constraints - Base Offset: 0 mm; Base Constraint: 00_begane grond_(AVL-BK); Base Extension Distance: 0 mm; Base is Attached: no; Related to Mass: no; Room Bounding: yes; Top Constraint: Up to level: 01_eerste verdieping_(RVL-OK); Top Extension Distance: 0 mm; Top Offset: 0 mm; Top is Attached: yes; Location Line: Wall Centerline; Unconnected Height: 3000 mm
Dimensions - Area: 14.7 m2; Length: 5100 mm; Volume: 1.47 m3
Phasing - Phase Created: nieuw
Structural - Structural: no; Structural Usage: Non-bearing
Cross-Section Definition - Cross-Section: Vertical
Name (Walls : Basic Wall :...) | ElementId
 RBS_22_WA_wand_binnen_d=100 | 691703
 RBS_22_WA_wand_binnen_d=100 | 691705

# IfcWindow: Windows : RBS_3-_WI_pui_glas_SH : buiten (3)
In: 00
Type - PredefinedType: WINDOW; Classification: 31.40 buitenwandopeningen; gevuld met puien, algemeen (verzamelniveau) (NL-SfB); Material: glas
Type - Other - Category: Windows; Family Name: RBS_3-_WI_pui_glas_SH
Type - Constraints - Default Elevation: 0 mm; type: RBS_57_AT_ventilatierooster_SH : buiten
Type - Construction - IsExternal[Type]: yes
Type - Identity Data - Assembly Code: 31.40; Assembly Description: buitenwandopeningen; gevuld met puien, algemeen (verzamelniveau); IfcExportAs[Type]: IfcWindow; IfcObjectType[Type]: raam; Type Mark: 26; Type Name: buiten
Type - Analytical Properties - Define Thermal Properties by: Schematic Type; Analytic Construction: <None>
Type - Pset_WindowCommon - IsExternal: yes
Type - RBS - IsExternal: yes; ObjectType: raam; Class: IfcWindow
OverallHeight: 80 mm
Pset_EnvironmentalImpactIndicators - Reference: buiten
Pset_WindowCommon - Reference: buiten
Qto_WindowBaseQuantities - Width: 20 mm
Other - Family: RBS_3-_WI_pui_glas_SH; Family and Type: RBS_3-_WI_pui_glas_SH: buiten; Type: buiten; Type Id: 645226
Constraints - Level: 00_begane grond_(AVL-BK); Moves With Nearby Elements: no; ventilatierooster_aan: no; Host: Level : 00_begane grond_(AVL-BK); ventilatierooster_uit: yes
Dimensions - b_overstek: 15 mm; d_paneel: 20 mm; d_ventilatierooster: 80 mm; h_ventilatierooster: 125 mm
Identity Data - Assembly Name: kozijncombinatie_buiten
Materials and Finishes - materiaal_ventilatierooster: RBS_staal_massief_gegalvaniseerd; materiaal_vlakvulling: RBS_glas_afwerking_dubbel glas_floatglas
Phasing - Phase Created: nieuw
Name (Windows : RBS_3-_WI_pui_glas_SH :...) | OverallWidth (mm) = Height (mm) = b_paneel (mm) | Perimeter (mm) | Qto_WindowBaseQuantities, Area (m2) = Dimensions, Area (m2) | Offset from Host (mm) | b_ventilatierooster (mm) | h_paneel (mm) | Volume (m3) | Mark
 buiten | 780 | 1600 | 3.7385 | 145 | 750 | 2390 | 0.037284 | 4
 buiten | 930 | 1900 | 0.66275 | 2145 | 900 | 390 | 0.007254 | 3
 buiten | 930 | 1900 | 1.11635 | 145 | 900 | 630 | 0.011718 | 1

# IfcWindow: Windows : RBS_3-_WI_raam_paneel_SH : links_buiten
In: 00
Type - PredefinedType: WINDOW; Classification: 31.40 buitenwandopeningen; gevuld met puien, algemeen (verzamelniveau) (NL-SfB); Material: hout, glas
Type - Windows : RBS_3-_WI_raam_paneel_SH : links_buiten:1 - OperationType: SIDEHUNGLEFTHAND
Type - Other - Category: Windows; Family Name: RBS_3-_WI_raam_paneel_SH
Type - Constraints - Default Elevation: 0 mm; draairichting: raam_draairichting : links_buiten
Type - Construction - IsExternal[Type]: yes
Type - Identity Data - Assembly Code: 31.40; Assembly Description: buitenwandopeningen; gevuld met puien, algemeen (verzamelniveau); IfcExportAs[Type]: IfcWindow; IfcObjectType[Type]: raam; PanelOperation1[Type]: SideHungLeftHand; Type Mark: 5; Type Name: links_buiten
Type - Analytical Properties - Analytic Construction: <None>; Define Thermal Properties by: Schematic Type
Type - Pset_WindowCommon - IsExternal: yes
Type - RBS - IsExternal: yes; ObjectType: raam; OperationType: SideHungLeftHand; Class: IfcWindow
OverallHeight: 398.079 mm; OverallWidth: 930 mm
Pset_EnvironmentalImpactIndicators - Reference: links_buiten
Pset_WindowCommon - Reference: links_buiten
Qto_WindowBaseQuantities - Width: 20 mm; Height: 790 mm; Perimeter: 1620 mm; Area: 9.35735 m2
Other - Family: RBS_3-_WI_raam_paneel_SH; Family and Type: RBS_3-_WI_raam_paneel_SH: links_buiten; Type: links_buiten; Type Id: 645205
Constraints - Level: 00_begane grond_(AVL-BK); aantal_roedes: 0; aantal_stijlen: 0; Host: Level : 00_begane grond_(AVL-BK); Moves With Nearby Elements: no; Offset from Host: 825 mm; ventilatierooster_aan: no
Dimensions - Area: 9.35735 m2; b_glas: 790 mm; b_paneel: 930 mm; b_roedes_paneel: 60 mm; b_roedes_vlakvulling: 30 mm; b_stijlen_paneel: 70 mm; b_stijlen_vlakvulling: 30 mm; b_ventilatierooster: 790 mm; d_glas: 20 mm; d_paneel: 80 mm; d_roedes_vlakvulling: 50 mm; d_stijlen_vlakvulling: 50 mm; h_glas: 1440 mm; h_paneel: 1560 mm; h_stijlen_vlakvulling: 1440 mm; h_stijlen_vlakvulling_ventilatierooster: 1315 mm; h_ventilatierooster: 125 mm; Volume: 0.12796 m3
Identity Data - Assembly Name: kozijncombinatie_buiten; Mark: 5
Materials and Finishes - materiaal_glas: RBS_glas_afwerking_dubbel glas_floatglas; materiaal_paneel: RBS_hout_massief_vuren; materiaal_ventilatierooster: RBS_staal_massief_gegalvaniseerd
Phasing - Phase Created: nieuw
Visibility - roedes_1: no; roedes_2: no; roedes_3: no; roedes_4: no; roedes_5: no; roedes_6: no; roedes_7: no; roedes_8: no; stijlen_1: no; stijlen_2: no; stijlen_3: no; stijlen_4: no; stijlen_5: no; stijlen_6: no; stijlen_7: no; stijlen_8: no

# Material: beton
Identity - Class: Generic
Other - Category: Materials
Identity Data - Cost: 0; IfcName: beton
Materials and Finishes - Color: 7895160; Glow: no; Name: RBS_beton_gen; Shininess: 64; Smoothness: 50; Transparency: 0

# Material: hout
Identity - Category: Hout; Class: Wood
Other - Category: Materials
Identity Data - Cost: 0; Description: vurenhout; IfcName: hout
Materials and Finishes - Glow: no; Transparency: 0; Color: 8303328; Name: RBS_hout_massief_vuren; Shininess: 64; Smoothness: 50

# Material: glas
Identity - Category: Glas; Class: Glass
Other - Category: Materials
Identity Data - Cost: 0; Description: glas; IfcName: glas
Materials and Finishes - Glow: no; Color: 15724780; Name: RBS_glas_afwerking_dubbel glas_floatglas; Shininess: 64; Smoothness: 50; Transparency: 85

# Material: hout
Identity - Category: Hout; Class: Wood
Other - Category: Materials
Identity Data - Cost: 0; Description: eikenhout; IfcName: hout
Materials and Finishes - Glow: no; Transparency: 0; Color: 8303328; Name: RBS_hout_massief_eiken; Shininess: 64; Smoothness: 50

# Material: divers
Identity - Class: Generic
Other - Category: Materials
Identity Data - Cost: 0; IfcName: divers
Materials and Finishes - Glow: no; Transparency: 0; Color: 7895160; Name: RBS_divers_gen; Shininess: 64; Smoothness: 50

# Material: generiek - kleur
Identity - Class: Generic
Other - Category: Materials
Identity Data - Cost: 0; IfcName: generiek - kleur
Materials and Finishes - Glow: no; Transparency: 0; Color: 13073152; Name: RBS_kleur_blauw_RGB (000-123-199); Shininess: 64; Smoothness: 50

# Material: generiek - kleur
Identity - Class: Generic
Other - Category: Materials
Identity Data - Cost: 0; IfcName: generiek - kleur
Materials and Finishes - Glow: no; Transparency: 0; Color: 1977301; Name: RBS_kleur_rood_RGB (213-043-030); Shininess: 64; Smoothness: 50
